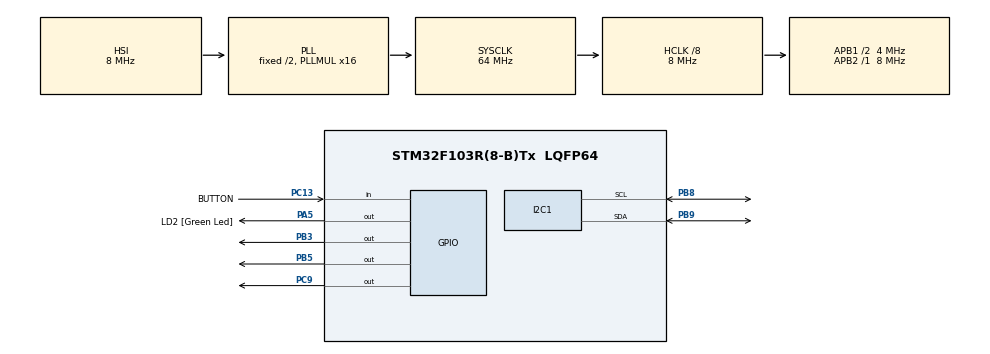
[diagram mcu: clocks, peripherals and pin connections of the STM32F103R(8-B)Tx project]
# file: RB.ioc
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Mcu.Family=STM32F1
Mcu.Name=STM32F103R(8-B)Tx
Mcu.Package=LQFP64
NVIC.PriorityGroup=NVIC_PRIORITYGROUP_4
NVIC.TIM2_IRQn=true\:0\:0\:false\:false\:true\:true\:true\:true
PA13.GPIO_Label=TMS
PA13.Mode=Serial_Wire
PA13.Signal=SYS_JTMS-SWDIO
PA14.GPIO_Label=TCK
PA14.Mode=Serial_Wire
PA14.Signal=SYS_JTCK-SWCLK
PA2.GPIO_Label=USART_TX
PA2.GPIO_Mode=GPIO_MODE_AF_PP
PA2.GPIO_PuPd=GPIO_NOPULL
PA2.GPIO_Speed=GPIO_SPEED_FREQ_LOW
PA2.Signal=USART2_TX
PA3.GPIO_Label=USART_RX
PA3.GPIO_Mode=GPIO_MODE_AF_PP
PA3.GPIO_PuPd=GPIO_NOPULL
PA3.GPIO_Speed=GPIO_SPEED_FREQ_LOW
PA3.Signal=USART2_RX
PA5.GPIO_Label=LD2 [Green Led]
PA5.GPIO_ModeDefaultOutputPP=GPIO_MODE_OUTPUT_PP
PA5.GPIO_PuPd=GPIO_NOPULL
PA5.GPIO_Speed=GPIO_SPEED_FREQ_LOW
PA5.Signal=GPIO_Output
PB3.Signal=GPIO_Output
PB5.Signal=GPIO_Output
PB8.Mode=I2C
PB8.Signal=I2C1_SCL
PB9.Mode=I2C
PB9.Signal=I2C1_SDA
PC13-TAMPER-RTC.GPIO_Label=BUTTON
PC13-TAMPER-RTC.GPIO_PuPd=GPIO_PULLUP
PC13-TAMPER-RTC.Signal=GPIO_Input
PC14-OSC32_IN.Mode=LSE-External-Oscillator
PC14-OSC32_IN.Signal=RCC_OSC32_IN
PC15-OSC32_OUT.Mode=LSE-External-Oscillator
PC15-OSC32_OUT.Signal=RCC_OSC32_OUT
PC9.Signal=GPIO_Output
PD0-OSC_IN.Mode=HSE-External-Clock-Source
PD0-OSC_IN.Signal=RCC_OSC_IN
PD1-OSC_OUT.Mode=HSE-External-Clock-Source
PD1-OSC_OUT.Signal=RCC_OSC_OUT
ProjectManager.HeapSize=0x200
ProjectManager.StackSize=0x400
ProjectManager.TargetToolchain=STM32CubeIDE
RCC.AHBCLKDivider=RCC_SYSCLK_DIV8
RCC.AHBFreq_Value=8000000
RCC.APB1CLKDivider=RCC_HCLK_DIV2
RCC.APB1Freq_Value=4000000
RCC.APB1TimFreq_Value=8000000
RCC.APB2Freq_Value=8000000
RCC.APB2TimFreq_Value=8000000
RCC.HCLKFreq_Value=8000000
RCC.PLLMUL=RCC_PLL_MUL16
RCC.RTCClockSelection=RCC_RTCCLKSOURCE_LSE
RCC.SYSCLKFreq_VALUE=64000000
RCC.SYSCLKSource=RCC_SYSCLKSOURCE_PLLCLK
RCC.USBFreq_Value=64000000
TIM2.Period=9
TIM2.Prescaler=63999
VP_TIM2_VS_ClockSourceINT.Mode=Internal
board=NUCLEO-F103RB

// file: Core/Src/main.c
/* USER CODE BEGIN Header */
/**
  ******************************************************************************
  * @file           : main.c
  * @brief          : Main program body
  ******************************************************************************
  * @attention
  *
  * Copyright (c) 2024 STMicroelectronics.
  * All rights reserved.
  *
  * This software is licensed under terms that can be found in the LICENSE file
  * in the root directory of this software component.
  * If no LICENSE file comes with this software, it is provided AS-IS.
  *
  ******************************************************************************
  */
/* USER CODE END Header */
#include "main.h"

/* USER CODE BEGIN Includes */
#include "input_processing.h"
#include "scheduler.h"
#include "led_display.h"
#include "i2c-lcd.h"
#include "global.h"
#include "fsm_auto.h"
#include "fsm_adjust.h"
#include "fsm_night.h"
#include "fsm_manual.h"
/* USER CODE END Includes */

I2C_HandleTypeDef hi2c1;

TIM_HandleTypeDef htim2;

void SystemClock_Config(void);
static void MX_GPIO_Init(void);
static void MX_TIM2_Init(void);
static void MX_I2C1_Init(void);

/* USER CODE BEGIN 0 */
void led(){
	HAL_GPIO_TogglePin(GPIOC, GPIO_PIN_9);

}
/* USER CODE END 0 */

int main(void)
{

  /* MCU Configuration--------------------------------------------------------*/

  /* Reset of all peripherals, Initializes the Flash interface and the Systick. */
  HAL_Init();

  /* Configure the system clock */
  SystemClock_Config();

  /* Initialize all configured peripherals */
  MX_GPIO_Init();
  MX_TIM2_Init();
  MX_I2C1_Init();
  /* USER CODE BEGIN 2 */
lcd_init();
  /* USER CODE END 2 */

  /* Infinite loop */
  /* USER CODE BEGIN WHILE */
  HAL_TIM_Base_Start_IT(&htim2);
  SCH_ADD_TASK(fsm_for_input_processing,10,10);
  SCH_ADD_TASK(fsm_auto, 3, 1000);
  SCH_ADD_TASK(fsm_adjust,10,10);
  SCH_ADD_TASK(fsm_night,40,1000);
  SCH_ADD_TASK(fsm_manual,40,1000);
  SCH_ADD_TASK(show,2,10);

  while (1)
  {
	  SCH_DISPATCH_TASK();
    /* USER CODE END WHILE */

  }
}

void SystemClock_Config(void)
{
  RCC_OscInitTypeDef RCC_OscInitStruct = {0};
  RCC_ClkInitTypeDef RCC_ClkInitStruct = {0};

  /** Initializes the RCC Oscillators according to the specified parameters
  * in the RCC_OscInitTypeDef structure.
  */
  RCC_OscInitStruct.OscillatorType = RCC_OSCILLATORTYPE_HSI;
  RCC_OscInitStruct.HSIState = RCC_HSI_ON;
  RCC_OscInitStruct.HSICalibrationValue = RCC_HSICALIBRATION_DEFAULT;
  RCC_OscInitStruct.PLL.PLLState = RCC_PLL_ON;
  RCC_OscInitStruct.PLL.PLLSource = RCC_PLLSOURCE_HSI_DIV2;
  RCC_OscInitStruct.PLL.PLLMUL = RCC_PLL_MUL16;
  if (HAL_RCC_OscConfig(&RCC_OscInitStruct) != HAL_OK)
  {
    Error_Handler();
  }

  /** Initializes the CPU, AHB and APB buses clocks
  */
  RCC_ClkInitStruct.ClockType = RCC_CLOCKTYPE_HCLK|RCC_CLOCKTYPE_SYSCLK
                              |RCC_CLOCKTYPE_PCLK1|RCC_CLOCKTYPE_PCLK2;
  RCC_ClkInitStruct.SYSCLKSource = RCC_SYSCLKSOURCE_PLLCLK;
  RCC_ClkInitStruct.AHBCLKDivider = RCC_SYSCLK_DIV8;
  RCC_ClkInitStruct.APB1CLKDivider = RCC_HCLK_DIV2;
  RCC_ClkInitStruct.APB2CLKDivider = RCC_HCLK_DIV1;

  if (HAL_RCC_ClockConfig(&RCC_ClkInitStruct, FLASH_LATENCY_2) != HAL_OK)
  {
    Error_Handler();
  }
}

static void MX_I2C1_Init(void)
{

  hi2c1.Instance = I2C1;
  hi2c1.Init.ClockSpeed = 100000;
  hi2c1.Init.DutyCycle = I2C_DUTYCYCLE_2;
  hi2c1.Init.OwnAddress1 = 0;
  hi2c1.Init.AddressingMode = I2C_ADDRESSINGMODE_7BIT;
  hi2c1.Init.DualAddressMode = I2C_DUALADDRESS_DISABLE;
  hi2c1.Init.OwnAddress2 = 0;
  hi2c1.Init.GeneralCallMode = I2C_GENERALCALL_DISABLE;
  hi2c1.Init.NoStretchMode = I2C_NOSTRETCH_DISABLE;
  if (HAL_I2C_Init(&hi2c1) != HAL_OK)
  {
    Error_Handler();
  }

}

static void MX_TIM2_Init(void)
{

  TIM_ClockConfigTypeDef sClockSourceConfig = {0};
  TIM_MasterConfigTypeDef sMasterConfig = {0};

  htim2.Instance = TIM2;
  htim2.Init.Prescaler = 7999;
  htim2.Init.CounterMode = TIM_COUNTERMODE_UP;
  htim2.Init.Period = 9;
  htim2.Init.ClockDivision = TIM_CLOCKDIVISION_DIV1;
  htim2.Init.AutoReloadPreload = TIM_AUTORELOAD_PRELOAD_DISABLE;
  if (HAL_TIM_Base_Init(&htim2) != HAL_OK)
  {
    Error_Handler();
  }
  sClockSourceConfig.ClockSource = TIM_CLOCKSOURCE_INTERNAL;
  if (HAL_TIM_ConfigClockSource(&htim2, &sClockSourceConfig) != HAL_OK)
  {
    Error_Handler();
  }
  sMasterConfig.MasterOutputTrigger = TIM_TRGO_RESET;
  sMasterConfig.MasterSlaveMode = TIM_MASTERSLAVEMODE_DISABLE;
  if (HAL_TIMEx_MasterConfigSynchronization(&htim2, &sMasterConfig) != HAL_OK)
  {
    Error_Handler();
  }

}

static void MX_GPIO_Init(void)
{
  GPIO_InitTypeDef GPIO_InitStruct = {0};

  /* GPIO Ports Clock Enable */
  __HAL_RCC_GPIOC_CLK_ENABLE();
  __HAL_RCC_GPIOD_CLK_ENABLE();
  __HAL_RCC_GPIOA_CLK_ENABLE();
  __HAL_RCC_GPIOB_CLK_ENABLE();

  /*Configure GPIO pin Output Level */
  HAL_GPIO_WritePin(LD2_GPIO_Port, LD2_Pin, GPIO_PIN_RESET);

  /*Configure GPIO pin Output Level */
  HAL_GPIO_WritePin(GPIOC, GPIO_PIN_9, GPIO_PIN_RESET);

  /*Configure GPIO pin Output Level */
  HAL_GPIO_WritePin(GPIOB, GPIO_PIN_3|GPIO_PIN_5, GPIO_PIN_RESET);

  /*Configure GPIO pin : BUTTON_Pin */
  GPIO_InitStruct.Pin = BUTTON_Pin;
  GPIO_InitStruct.Mode = GPIO_MODE_INPUT;
  GPIO_InitStruct.Pull = GPIO_PULLUP;
  HAL_GPIO_Init(BUTTON_GPIO_Port, &GPIO_InitStruct);

  /*Configure GPIO pins : USART_TX_Pin USART_RX_Pin */
  GPIO_InitStruct.Pin = USART_TX_Pin|USART_RX_Pin;
  GPIO_InitStruct.Mode = GPIO_MODE_AF_PP;
  GPIO_InitStruct.Speed = GPIO_SPEED_FREQ_LOW;
  HAL_GPIO_Init(GPIOA, &GPIO_InitStruct);

  /*Configure GPIO pin : LD2_Pin */
  GPIO_InitStruct.Pin = LD2_Pin;
  GPIO_InitStruct.Mode = GPIO_MODE_OUTPUT_PP;
  GPIO_InitStruct.Pull = GPIO_NOPULL;
  GPIO_InitStruct.Speed = GPIO_SPEED_FREQ_LOW;
  HAL_GPIO_Init(LD2_GPIO_Port, &GPIO_InitStruct);

  /*Configure GPIO pin : PC9 */
  GPIO_InitStruct.Pin = GPIO_PIN_9;
  GPIO_InitStruct.Mode = GPIO_MODE_OUTPUT_PP;
  GPIO_InitStruct.Pull = GPIO_NOPULL;
  GPIO_InitStruct.Speed = GPIO_SPEED_FREQ_LOW;
  HAL_GPIO_Init(GPIOC, &GPIO_InitStruct);

  /*Configure GPIO pins : PB3 PB5 */
  GPIO_InitStruct.Pin = GPIO_PIN_3|GPIO_PIN_5;
  GPIO_InitStruct.Mode = GPIO_MODE_OUTPUT_PP;
  GPIO_InitStruct.Pull = GPIO_NOPULL;
  GPIO_InitStruct.Speed = GPIO_SPEED_FREQ_LOW;
  HAL_GPIO_Init(GPIOB, &GPIO_InitStruct);
  /*Configure GPIO pin Output Level */
  HAL_GPIO_WritePin(GPIOB, red1_Pin|yellow1_Pin|green1_Pin|red2_Pin
                          |yellow2_Pin|green2_Pin|EN1_Pin|EN2_Pin
                          |EN3_Pin|EN4_Pin|mode_Pin|GPIO_PIN_6, GPIO_PIN_RESET);

  HAL_GPIO_WritePin(GPIOC, GPIO_PIN_7, GPIO_PIN_RESET);

  /* Configure GPIO pins for GPIOB: PC7 */
    GPIO_InitStruct.Pin = GPIO_PIN_7;
    GPIO_InitStruct.Mode = GPIO_MODE_OUTPUT_PP;
    GPIO_InitStruct.Pull = GPIO_NOPULL;
    GPIO_InitStruct.Speed = GPIO_SPEED_FREQ_LOW;
    HAL_GPIO_Init(GPIOC, &GPIO_InitStruct);

     /* Configure GPIO pins for GPIOB: PC7 */
	GPIO_InitStruct.Pin = GPIO_PIN_0;
	GPIO_InitStruct.Mode = GPIO_MODE_INPUT;
	GPIO_InitStruct.Pull = GPIO_PULLUP;
	HAL_GPIO_Init(GPIOB, &GPIO_InitStruct);

  /* Configure GPIO pins for GPIOB: PB6 */
  GPIO_InitStruct.Pin = GPIO_PIN_6;
  GPIO_InitStruct.Mode = GPIO_MODE_OUTPUT_PP;
  GPIO_InitStruct.Pull = GPIO_NOPULL;
  GPIO_InitStruct.Speed = GPIO_SPEED_FREQ_LOW;
  HAL_GPIO_Init(GPIOB, &GPIO_InitStruct);

  /* Configure other GPIO pins as needed */
  GPIO_InitStruct.Pin = red1_Pin|yellow1_Pin|green1_Pin|red2_Pin
                          |yellow2_Pin|green2_Pin|EN1_Pin|EN2_Pin
                          |EN3_Pin|EN4_Pin|mode_Pin;
  GPIO_InitStruct.Mode = GPIO_MODE_OUTPUT_PP;
  GPIO_InitStruct.Pull = GPIO_NOPULL;
  GPIO_InitStruct.Speed = GPIO_SPEED_FREQ_LOW;
  HAL_GPIO_Init(GPIOB, &GPIO_InitStruct);

  /* Configure input pins for buttons */
  GPIO_InitStruct.Pin = BUTTON_1_Pin|BUTTON_2_Pin;
  GPIO_InitStruct.Mode = GPIO_MODE_INPUT;
  GPIO_InitStruct.Pull = GPIO_PULLUP;
  HAL_GPIO_Init(GPIOB, &GPIO_InitStruct);

  GPIO_InitStruct.Pin = BUTTON_3_Pin|BUTTON_4_Pin;
    GPIO_InitStruct.Mode = GPIO_MODE_INPUT;
    GPIO_InitStruct.Pull = GPIO_PULLUP;
    HAL_GPIO_Init(GPIOA, &GPIO_InitStruct);
}

/* USER CODE BEGIN 4 */
void HAL_TIM_PeriodElapsedCallback(TIM_HandleTypeDef * htim){
	SCH_UPDATE();
}
/* USER CODE END 4 */

void Error_Handler(void)
{
  __disable_irq();
  while (1)
  {
  }
}
